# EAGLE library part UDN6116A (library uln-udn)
DRIVER ARRAY

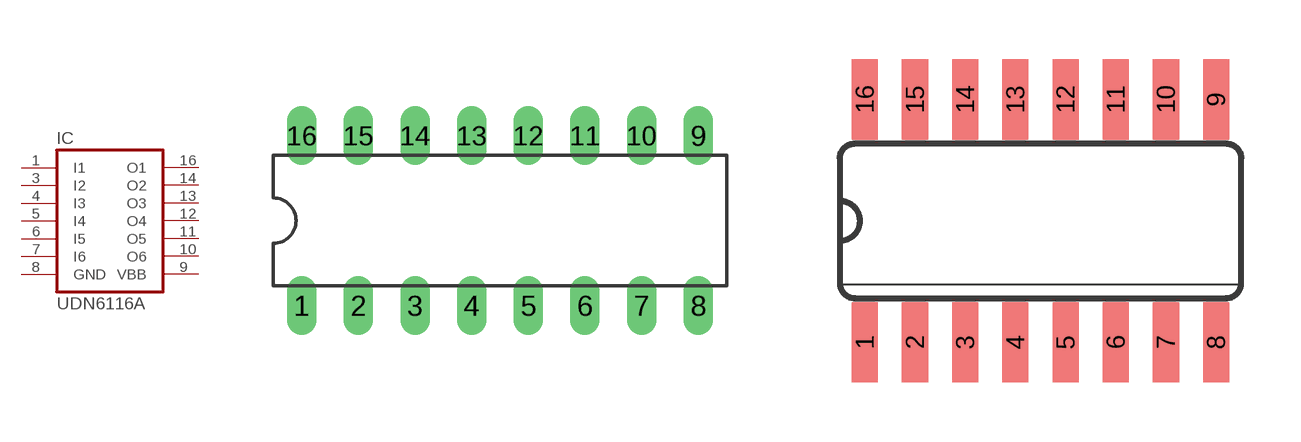
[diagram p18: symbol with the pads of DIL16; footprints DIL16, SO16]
Designator prefix IC

## UDN6116AN  [DIL16]
1  I1  in
3  I2  in
4  I3  in
5  I4  in
6  I5  in
7  I6  in
8  GND  pwr
9  VBB  pas
10  O6  oc
11  O5  oc
12  O4  oc
13  O3  oc
14  O2  oc
16  O1  oc

## UDN6116AD  [SO16]
Pads as for DIL16

## Footprint DIL16 (pad centres in mm)
Dual In Line Package
drill 0.813 long: 1 -8.89,-3.81; 2 -6.35,-3.81; 3 -3.81,-3.81; 4 -1.27,-3.81; 5 1.27,-3.81; 6 3.81,-3.81; 7 6.35,-3.81; 8 8.89,-3.81; 9 8.89,3.81; 10 6.35,3.81; 11 3.81,3.81; 12 1.27,3.81; 13 -1.27,3.81; 14 -3.81,3.81; 15 -6.35,3.81; 16 -8.89,3.81

## Footprint SO16 (pad centres in mm)
Small Outline Package
smd 0.66 x 2.032: 1 -4.445,-3.073; 2 -3.175,-3.073; 3 -1.905,-3.073; 4 -0.635,-3.073; 5 0.635,-3.073; 6 1.905,-3.073; 7 3.175,-3.073; 8 4.445,-3.073; 9 4.445,3.073; 10 3.175,3.073; 11 1.905,3.073; 12 0.635,3.073; 13 -0.635,3.073; 14 -1.905,3.073; 15 -3.175,3.073; 16 -4.445,3.073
